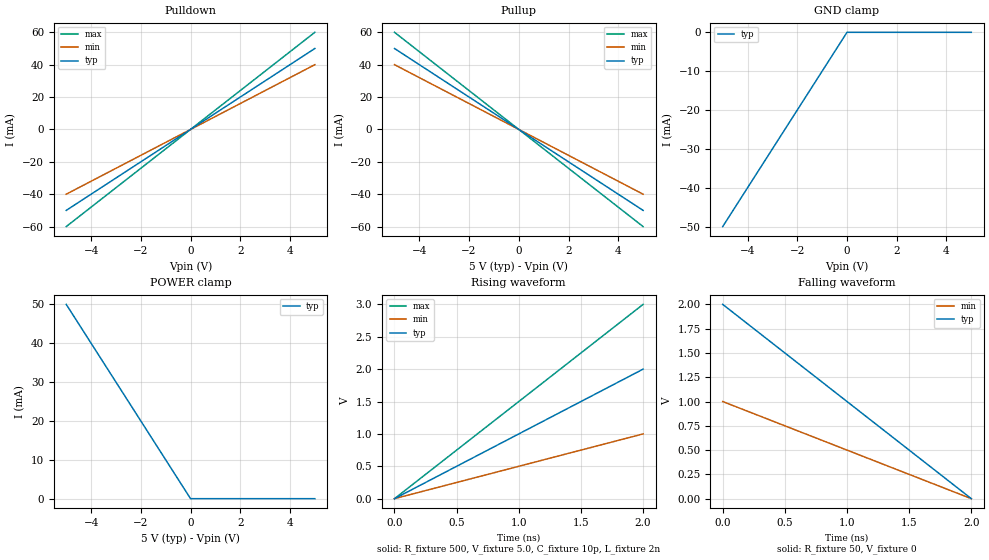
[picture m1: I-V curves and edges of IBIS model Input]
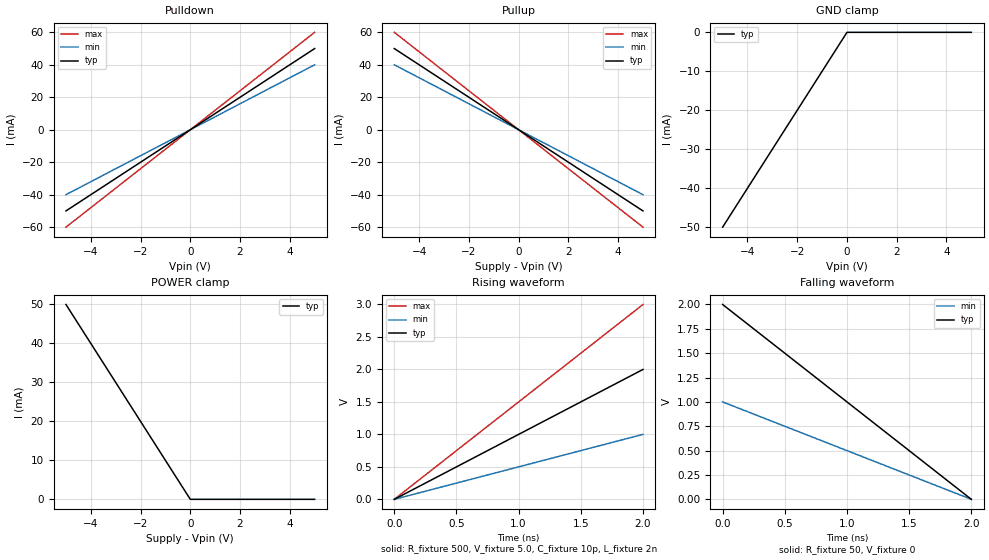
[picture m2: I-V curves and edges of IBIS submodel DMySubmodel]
[IBIS Ver]   3.2  |Let's test a comment
[Comment char]  #_char
[File name]   ibis_v2_1.pkg
[File Rev]   1.0  #Let's test a comment
[Date]   26/08/2021
[Source]   This is the
   source for the files
[Notes]   We can have some
   Notes
[Copyright] /*
 * This program source code file is part of KiCad, a free EDA CAD application.
 * Copyright (C) 2017-2021 KiCad Developers, see AUTHORS.txt for contributors.
 * This program is free software; you can redistribute it and/or
 * modify it under the terms of the GNU General Public License
 * as published by the Free Software Foundation; either version 2
 * of the License, or (at your option) any later version.
 * This program is distributed in the hope that it will be useful,
 * but WITHOUT ANY WARRANTY; without even the implied warranty of
 * MERCHANTABILITY or FITNESS FOR A PARTICULAR PURPOSE.  See the
 * GNU General Public License for more details.
 * You should have received a copy of the GNU General Public License
 * along with this program; if not, you may find one here:
 * http://www.gnu.org/licenses/old-licenses/gpl-2.0.html
 * or you may search the http://www.gnu.org website for the version 2 license,
 * or you may write to the Free Software Foundation, Inc.,
 * 51 Franklin Street, Fifth Floor, Boston, MA  02110-1301, USA
 */
[Disclaimer] This is NOT a valid component.
[Component]   Virtual
[Manufacturer]  KiCad
[Package]
R_pkg   1m   0.8m   2m
L_pkg   1m   0.8m   2m
C_pkg   1m   0.8m   2m
[Pin]   signal_name   model_name   R_pin   L_pin   C_pin
  1   VCC   POWER   1m   0.8m   2m
  2   GND   GND   1m   0.8m   2m
  3   X   Input   1m   0.8m   2m
  4   Y   Output   1m   0.8m   2m
  5   YN   Output   1m   0.8m   2m
  6   Y   Output   1m   0.8m   2m
  7   YN   Output   1m   0.8m   2m
[Package Model]   QS-SMT-cer-8-pin-pkgs
[Pin Mapping]  pulldown_ref   pullup_ref   gnd_clamp_ref  power_clamp_ref
1   GNDBUS   NC
2   NC   PWRBUS
3   GNDBUS   PWRBUS
4   GNDBUS   PWRBUS   GNDBUS   PWRBUS
5   GNDBUS   PWRBUS   GNDBUS   PWRBUS
6   GNDBUS   PWRBUS   GNDBUS   PWRBUS
7   GNDBUS   PWRBUS   GNDBUS   PWRBUS
[Diff Pin]  inv_pin  vdiff  tdelay_typ tdelay_min tdelay_max
 4   5   150mV   -1ns   0ns   -2ns
 6   7   150mV   -1ns   0ns   -2ns
# Models and submodels in the file (2): Input (Input), DMySubmodel (Dynamic_clamp)
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#[Series Pin Mapping]  pin_2   model_name   function_table_group
#  4   5   PinSeries   1
#  6   7   PinSeries   2
#[Series Switch Groups]
#On 4 5 /
#Off 4 5 /
#On 4 5 6 7 /
#Off 4 5 6 7 /
[Model]   Input
Model_type   Input
Polarity   Non-Inverting
Enable   Active-High
Vinl = 0.8V
Vinh = 2.0V
Vmeas= 1.5V
Cref =50pF
Rref=500
Vref = 0
C_comp   10.0pF   8.0pF   15.0pF
[Model Spec]
#   Subparameter   typ   min   max
Vinh   3.5   3.15   3.85
Vinl   1.5   1.35   1.65
Vinh+   2.0   NA   NA   | Overrides the
Vinh-   1.6   NA   NA   | thresholds
Vinl+   1.1   NA   NA
Vinl-   0.6   NA   NA   | All 4 are required
S_overshoot_high   5.5   5.0   6.0   | Static overshoot
S_overshoot_low   -0.5   NA   NA
D_overshoot_high   6.0   5.5   6.5   | Dynamic overshoot
D_overshoot_low   -1.0   -1.0   -1.0
D_overshoot_time   20n   20n   20n   | & static overshoot
Pulse_high   3V   NA   NA   | Pulse immunity
Pulse_low   0   NA   NA   | requires
Pulse_time   3n   NA   NA   | Pulse_time
Vmeas   3.68   3.18   4.68   | A 5 volt PECL
[Add Submodel]
# Submodel_name   Mode
Bus_Hold_1   Non-Driving
Dynamic_clamp_1   All
[Driver Schedule]
# Model_name   Rise_on_dly  Rise_off_dly  Fall_on_dly  Fall_off_dly
  MODEL_OUT   0.0ns   NA   0.0ns   NA
  M_O_SOURCE1   0.5ns   NA   0.5ns   NA
#   low (high-Z) to high   high to low (high-Z)
  M_O_SOURCE2   0.5n   1.5n   NA   NA
#   low to high to low   low (high-Z)
  M_O_DRAIN1   1.0n   NA   1.5n   NA
#   low to high (high-Z)   high (high-Z) to low
  M_O_DRAIN2   NA   NA   1.5n   2.0n
|   high (high-Z)   high to low to high
[Voltage range]   5.0V   4.5V   5.5V
[Temperature Range]   27.0   -50   130.0
[Pullup Reference]   5.0V   4.5V   5.5V
[Pulldown Reference]   0V   0V   0V
[POWER Clamp Reference] 5.0V   4.5V   5.5V
[GND Clamp Reference]   0V   0V   0V
[TTgnd]   10n   12n   9n
[TTpower]   12n   NA   NA
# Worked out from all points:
#   slope of the pulldown table from 0 to 0.75 V, typ, clamps not added: 100 ohm
#   slope of the pullup table from 0 to 0.75 V, typ, clamps not added: 100 ohm
#   rising waveform, R_fixture 500, V_fixture 5.0, C_fixture 10p, L_fixture 2n: 20-80 % time 1.2ns typ, 1.2ns min, 1.2ns max; typ from 0 V to 2 V
#   falling waveform, R_fixture 50, V_fixture 0: 20-80 % time 1.2ns typ, 1.2ns min, NA max; typ from 2 V to 0 V
[Pulldown]
#  Voltage   I(typ)   I(min)   I(max)
-5V       -50mA      -40mA      -60mA
0V        0A         0A         0A
5V        50mA       40mA       60mA
[Pullup]
#  Voltage   I(typ)   I(min)   I(max)
-5V       50mA       40mA       60mA
0V        0A         0A         0A
5V        -50mA      -40mA      -60mA
[GND_clamp]
#  Voltage   I(typ)   I(min)   I(max)
-5V       -50mA      NA         NA
0V        0A         NA         NA
5V        0A         NA         NA
[POWER_clamp]
#  Voltage   I(typ)   I(min)   I(max)
-5V       50mA       NA         NA
0V        0A         NA         NA
5V        0A         NA         NA
[Rgnd]   1500hm   100Ohm   3600
[Rpower]   150Ohm   100Ohm   NA
[Rac]   30Ohm   NA   NA
[Cac]   50pF   NA   NA
[On]
| variable   R(typ)   R(min)   R(max)
[R Series]   8ohm   6ohm   12ohm
|
| variable   L(typ)   L(min)   L(max)
[L Series]   5nH   NA   NA
| variable   R(typ)   R(min)   R(max)
[Rl Series]   4ohm   NA   NA
|
| variable   C(typ)   C(min)   C(max)  | The other elements
[C Series]   50pF   NA   NA   | are 0 impedance
[Off]
| variable   R(typ)   R(min)   R(max)
[R Series]   8ohm   6ohm   12ohm
|
| variable   L(typ)   L(min)   L(max)
[L Series]   5nH   NA   NA
| variable   R(typ)   R(min)   R(max)
[Rl Series]   4ohm   NA   NA
|
| variable   C(typ)   C(min)   C(max)  | The other elements
[C Series]   50pF   NA   NA   | are 0 impedance
[Off]
| variable   R(typ)   R(min)   R(max)
[R Series]   8ohm   6ohm   12ohm
|
| variable   L(typ)   L(min)   L(max)
[L Series]   5nH   NA   NA
| variable   R(typ)   R(min)   R(max)
[Rl Series]   4ohm   NA   NA
|
| variable   C(typ)   C(min)   C(max)  | The other elements
[C Series]   50pF   NA   NA   | are 0 impedance
[Off]
| variable   R(typ)   R(min)   R(max)
[R Series]   8ohm   6ohm   12ohm
|
| variable   L(typ)   L(min)   L(max)
[L Series]   5nH   NA   NA
| variable   R(typ)   R(min)   R(max)
[Rl Series]   4ohm   NA   NA
|
| variable   C(typ)   C(min)   C(max)  | The other elements
[C Series]   50pF   NA   NA   | are 0 impedance
[Ramp]
# variable   typ   min   max
dV/dt_r   3.0/2n   2.8/3n   3.2/1n
dV/dt_f   3.0/2n   2.8/3n   3.2/1n
[Rising Waveform]
R_fixture = 500
V_fixture = 5.0
C_fixture = 10p
L_fixture = 2n
C_dut = 7p
R_dut = 1m
L_dut = 1n
#Time   V(typ)   V(min)   V(max)
0s        0V         0V         0V
1ns       1V         500mV      1.5V
2ns       2V         1V         3V
[Falling Waveform]
R_fixture = 50
V_fixture = 0
#Time   V(typ)   V(min)   V(max)
0s        2V         1V         NA
1ns       1V         500mV      NA
2ns       0V         0V         NA
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[Submodel]   DMySubmodel
Submodel_type   Dynamic_clamp
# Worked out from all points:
#   slope of the pulldown table from 0 to 0.3 V, typ, clamps not added: 100 ohm
#   slope of the pullup table from 0 to 0.3 V, typ, clamps not added: 100 ohm
#   rising waveform, R_fixture 500, V_fixture 5.0, C_fixture 10p, L_fixture 2n: 20-80 % time 1.2ns typ, 1.2ns min, 1.2ns max; typ from 0 V to 2 V
#   falling waveform, R_fixture 50, V_fixture 0: 20-80 % time 1.2ns typ, 1.2ns min, NA max; typ from 2 V to 0 V
[Pulldown]
#  Voltage   I(typ)   I(min)   I(max)
-5V       -50mA      -40mA      -60mA
0V        0A         0A         0A
5V        50mA       40mA       60mA
[Pullup]
#  Voltage   I(typ)   I(min)   I(max)
-5V       50mA       40mA       60mA
0V        0A         0A         0A
5V        -50mA      -40mA      -60mA
[GND_clamp]
#  Voltage   I(typ)   I(min)   I(max)
-5V       -50mA      NA         NA
0V        0A         NA         NA
5V        0A         NA         NA
[POWER_clamp]
#  Voltage   I(typ)   I(min)   I(max)
-5V       50mA       NA         NA
0V        0A         NA         NA
5V        0A         NA         NA
[Ramp]
# variable   typ   min   max
dV/dt_r   3.0/2n   2.8/3n   3.2/1n
dV/dt_f   3.0/2n   2.8/3n   3.2/1n
[Rising Waveform]
R_fixture = 500
V_fixture = 5.0
C_fixture = 10p
L_fixture = 2n
C_dut = 7p
R_dut = 1m
L_dut = 1n
#Time   V(typ)   V(min)   V(max)
0s        0V         0V         0V
1ns       1V         500mV      1.5V
2ns       2V         1V         3V
[Falling Waveform]
R_fixture = 50
V_fixture = 0
#Time   V(typ)   V(min)   V(max)
0s        2V         1V         NA
1ns       1V         500mV      NA
2ns       0V         0V         NA
[Submodel Spec]
|   Subparameter   typ   min   max
V_trigger_r   3.1   2.4   3.7 | Low to high transition
   | triggers the turn on
   | process of the pullup
V_trigger_f   -10.0   -10.0   -10.0 | Not used, so trigger
   | voltages are set out
   | of range
Off_delay   5n   6n   4n  | Time from rising edge
   | trigger at which the
   | pullup turned off
[GND Clamp]   | Table to be offset
|
|  Voltage   I(typ)   I(min)   I(max)
|
-5V       -33A       -30A       -35A
-4V       -23A       -22A       -24A
-3V       -13A       -12A       -14A
-2V       -3A        -2.3A      -3.7A
-1.8V     -1.3A      -860mA     -1.9A
-1.7V     -680mA     -400mA     -1.1A
-1.6V     -280mA     -180mA     -510mA
-1.5V     -120mA     -98mA      -180mA
-1.4V     -75mA      -71mA      -83mA
-900mV    -18.5mA    -21mA      -16.5mA
5V        0A         0A         0A
[POWER Clamp]   | Table to be offset
|
|  Voltage   I(typ)   I(min)   I(max)
|
-5V       11.5A      11A        11.5A
-4V       7.8A       7.5A       8.15A
-3V       4.35A      4.1A       4.7A
-2V       1.1A       875mA      1.3A
-1.8V     530mA      370mA      725mA
-1.7V     290mA      180mA      450mA
-1.6V     120mA      68.5mA     220mA
-1.5V     36.5mA     24mA       69mA
-1.4V     12mA       11mA       16mA
0V        0A         0A         0A
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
